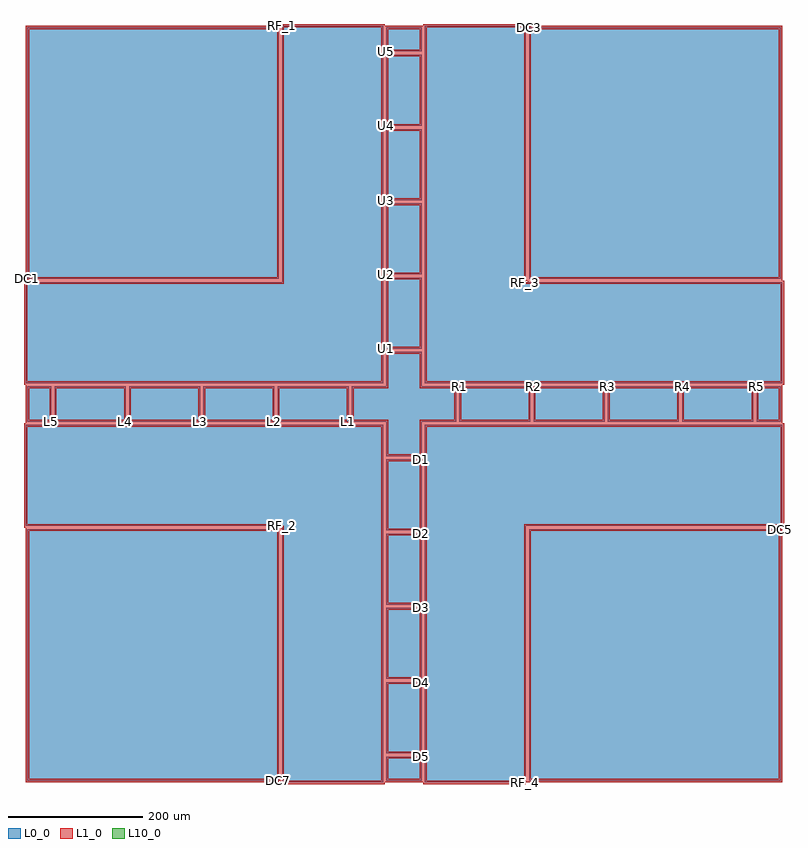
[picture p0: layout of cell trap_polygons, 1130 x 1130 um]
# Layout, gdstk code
import gdstk
lib = gdstk.Library(unit=1e-6, precision=1e-09)
def P(c, l, *ps):  # polygons
    for p in ps: c.add(gdstk.Polygon(p, *l))
L0_0 = (0, 0)
L1_0 = (1, 0)
L10_0 = (10, 0)

trap_polygons = lib.new_cell('trap_polygons')
P(trap_polygons, L0_0, [(-186.125,-560),(-560,-560),(-560,-186.125),(-186.125,-186.125),(-186.125,-560)],
  [(560,-186.125),(560,-560),(186.125,-560),(186.125,-186.125),(560,-186.125)],
  [(186.125,560),(560,560),(560,186.125),(186.125,186.125),(186.125,560)],
  [(-560,186.125),(-560,560),(-186.125,560),(-186.125,186.125),(-560,186.125)],
  [(-26.125,524.2),(-26.125,559.85),(26.125,559.85),(26.125,524.2),(-26.125,524.2)],
  [(524.2,26.125),(559.85,26.125),(559.85,-26.125),(524.2,-26.125),(524.2,26.125)],
  [(26.125,-524.2),(26.125,-559.85),(-26.125,-559.85),(-26.125,-524.2),(26.125,-524.2)],
  [(-524.2,-26.125),(-559.85,-26.125),(-559.85,26.125),(-524.2,26.125),(-524.2,-26.125)],
  [(-26.125,413.75),(-26.125,519.2),(26.125,519.2),(26.125,413.75),(-26.125,413.75)],
  [(413.75,26.125),(519.2,26.125),(519.2,-26.125),(413.75,-26.125),(413.75,26.125)],
  [(26.125,-413.75),(26.125,-519.2),(-26.125,-519.2),(-26.125,-413.75),(26.125,-413.75)],
  [(-413.75,-26.125),(-519.2,-26.125),(-519.2,26.125),(-413.75,26.125),(-413.75,-26.125)],
  [(-26.125,303.3),(-26.125,408.75),(26.125,408.75),(26.125,303.3),(-26.125,303.3)],
  [(303.3,26.125),(408.75,26.125),(408.75,-26.125),(303.3,-26.125),(303.3,26.125)],
  [(26.125,-303.3),(26.125,-408.75),(-26.125,-408.75),(-26.125,-303.3),(26.125,-303.3)],
  [(-303.3,-26.125),(-408.75,-26.125),(-408.75,26.125),(-303.3,26.125),(-303.3,-26.125)],
  [(-26.125,192.85),(-26.125,298.3),(26.125,298.3),(26.125,192.85),(-26.125,192.85)],
  [(192.85,26.125),(298.3,26.125),(298.3,-26.125),(192.85,-26.125),(192.85,26.125)],
  [(26.125,-192.85),(26.125,-298.3),(-26.125,-298.3),(-26.125,-192.85),(26.125,-192.85)],
  [(-192.85,-26.125),(-298.3,-26.125),(-298.3,26.125),(-192.85,26.125),(-192.85,-26.125)],
  [(-26.125,82.4),(-26.125,187.85),(26.125,187.85),(26.125,82.4),(-26.125,82.4)],
  [(82.4,26.125),(187.85,26.125),(187.85,-26.125),(82.4,-26.125),(82.4,26.125)],
  [(26.125,-82.4),(26.125,-187.85),(-26.125,-187.85),(-26.125,-82.4),(26.125,-82.4)],
  [(-82.4,-26.125),(-187.85,-26.125),(-187.85,26.125),(-82.4,26.125),(-82.4,-26.125)],
  [(-26.125,77.4),(26.125,77.4),(26.125,26.125),(77.4,26.125),(77.4,-26.125),(26.125,-26.125),(26.125,-77.4),(-26.125,-77.4),(-26.125,-26.125),(-77.4,-26.125),(-77.4,26.125),(-26.125,26.125),(-26.125,77.4)],
  [(181.125,-562.5),(31.125,-562.5),(31.125,-31.125),(562.5,-31.125),(562.5,-181.125),(181.125,-181.125),(181.125,-562.5)],
  [(181.125,181.125),(562.5,181.125),(562.5,31.125),(31.125,31.125),(31.125,562.5),(181.125,562.5),(181.125,181.125)],
  [(-181.125,-181.125),(-562.5,-181.125),(-562.5,-31.125),(-31.125,-31.125),(-31.125,-562.5),(-181.125,-562.5),(-181.125,-181.125)],
  [(-181.125,562.5),(-31.125,562.5),(-31.125,31.125),(-562.5,31.125),(-562.5,181.125),(-181.125,181.125),(-181.125,562.5)])
P(trap_polygons, L1_0, [(-186.125,-562.5),(-186.125,-557.5),(-557.5,-557.5),(-557.5,-188.625),(-188.625,-188.625),(-188.625,-560),(-183.625,-560),(-183.625,-183.625),(-562.5,-183.625),(-562.5,-562.5)],
  [(562.5,-186.125),(557.5,-186.125),(557.5,-557.5),(188.625,-557.5),(188.625,-188.625),(560,-188.625),(560,-183.625),(183.625,-183.625),(183.625,-562.5),(562.5,-562.5)],
  [(186.125,562.5),(186.125,557.5),(557.5,557.5),(557.5,188.625),(188.625,188.625),(188.625,560),(183.625,560),(183.625,183.625),(562.5,183.625),(562.5,562.5)],
  [(-562.5,186.125),(-557.5,186.125),(-557.5,557.5),(-188.625,557.5),(-188.625,188.625),(-560,188.625),(-560,183.625),(-183.625,183.625),(-183.625,562.5),(-562.5,562.5)],
  [(-28.625,524.2),(-23.625,524.2),(-23.625,557.35),(23.625,557.35),(23.625,526.7),(-26.125,526.7),(-26.125,521.7),(28.625,521.7),(28.625,562.35),(-28.625,562.35)],
  [(524.2,28.625),(524.2,23.625),(557.35,23.625),(557.35,-23.625),(526.7,-23.625),(526.7,26.125),(521.7,26.125),(521.7,-28.625),(562.35,-28.625),(562.35,28.625)],
  [(28.625,-524.2),(23.625,-524.2),(23.625,-557.35),(-23.625,-557.35),(-23.625,-526.7),(26.125,-526.7),(26.125,-521.7),(-28.625,-521.7),(-28.625,-562.35),(28.625,-562.35)],
  [(-524.2,-28.625),(-524.2,-23.625),(-557.35,-23.625),(-557.35,23.625),(-526.7,23.625),(-526.7,-26.125),(-521.7,-26.125),(-521.7,28.625),(-562.35,28.625),(-562.35,-28.625)],
  [(-28.625,413.75),(-23.625,413.75),(-23.625,516.7),(23.625,516.7),(23.625,416.25),(-26.125,416.25),(-26.125,411.25),(28.625,411.25),(28.625,521.7),(-28.625,521.7)],
  [(413.75,28.625),(413.75,23.625),(516.7,23.625),(516.7,-23.625),(416.25,-23.625),(416.25,26.125),(411.25,26.125),(411.25,-28.625),(521.7,-28.625),(521.7,28.625)],
  [(28.625,-413.75),(23.625,-413.75),(23.625,-516.7),(-23.625,-516.7),(-23.625,-416.25),(26.125,-416.25),(26.125,-411.25),(-28.625,-411.25),(-28.625,-521.7),(28.625,-521.7)],
  [(-413.75,-28.625),(-413.75,-23.625),(-516.7,-23.625),(-516.7,23.625),(-416.25,23.625),(-416.25,-26.125),(-411.25,-26.125),(-411.25,28.625),(-521.7,28.625),(-521.7,-28.625)],
  [(-28.625,303.3),(-23.625,303.3),(-23.625,406.25),(23.625,406.25),(23.625,305.8),(-26.125,305.8),(-26.125,300.8),(28.625,300.8),(28.625,411.25),(-28.625,411.25)],
  [(303.3,28.625),(303.3,23.625),(406.25,23.625),(406.25,-23.625),(305.8,-23.625),(305.8,26.125),(300.8,26.125),(300.8,-28.625),(411.25,-28.625),(411.25,28.625)],
  [(28.625,-303.3),(23.625,-303.3),(23.625,-406.25),(-23.625,-406.25),(-23.625,-305.8),(26.125,-305.8),(26.125,-300.8),(-28.625,-300.8),(-28.625,-411.25),(28.625,-411.25)],
  [(-303.3,-28.625),(-303.3,-23.625),(-406.25,-23.625),(-406.25,23.625),(-305.8,23.625),(-305.8,-26.125),(-300.8,-26.125),(-300.8,28.625),(-411.25,28.625),(-411.25,-28.625)],
  [(-28.625,192.85),(-23.625,192.85),(-23.625,295.8),(23.625,295.8),(23.625,195.35),(-26.125,195.35),(-26.125,190.35),(28.625,190.35),(28.625,300.8),(-28.625,300.8)],
  [(192.85,28.625),(192.85,23.625),(295.8,23.625),(295.8,-23.625),(195.35,-23.625),(195.35,26.125),(190.35,26.125),(190.35,-28.625),(300.8,-28.625),(300.8,28.625)],
  [(28.625,-192.85),(23.625,-192.85),(23.625,-295.8),(-23.625,-295.8),(-23.625,-195.35),(26.125,-195.35),(26.125,-190.35),(-28.625,-190.35),(-28.625,-300.8),(28.625,-300.8)],
  [(-192.85,-28.625),(-192.85,-23.625),(-295.8,-23.625),(-295.8,23.625),(-195.35,23.625),(-195.35,-26.125),(-190.35,-26.125),(-190.35,28.625),(-300.8,28.625),(-300.8,-28.625)],
  [(-28.625,82.4),(-23.625,82.4),(-23.625,185.35),(23.625,185.35),(23.625,84.9),(-26.125,84.9),(-26.125,79.9),(28.625,79.9),(28.625,190.35),(-28.625,190.35)],
  [(82.4,28.625),(82.4,23.625),(185.35,23.625),(185.35,-23.625),(84.9,-23.625),(84.9,26.125),(79.9,26.125),(79.9,-28.625),(190.35,-28.625),(190.35,28.625)],
  [(28.625,-82.4),(23.625,-82.4),(23.625,-185.35),(-23.625,-185.35),(-23.625,-84.9),(26.125,-84.9),(26.125,-79.9),(-28.625,-79.9),(-28.625,-190.35),(28.625,-190.35)],
  [(-82.4,-28.625),(-82.4,-23.625),(-185.35,-23.625),(-185.35,23.625),(-84.9,23.625),(-84.9,-26.125),(-79.9,-26.125),(-79.9,28.625),(-190.35,28.625),(-190.35,-28.625)],
  [(-26.125,79.9),(-26.125,74.9),(23.625,74.9),(23.625,23.625),(74.9,23.625),(74.9,-23.625),(23.625,-23.625),(23.625,-74.9),(-23.625,-74.9),(-23.625,-23.625),(-74.9,-23.625),(-74.9,23.625),(-23.625,23.625),(-23.625,77.4),(-28.625,77.4),(-28.625,28.625),(-79.9,28.625),(-79.9,-28.625),(-28.625,-28.625),(-28.625,-79.9),(28.625,-79.9),(28.625,-28.625),(79.9,-28.625),(79.9,28.625),(28.625,28.625),(28.625,79.9)],
  [(181.125,-565),(181.125,-560),(33.625,-560),(33.625,-33.625),(560,-33.625),(560,-178.625),(178.625,-178.625),(178.625,-562.5),(183.625,-562.5),(183.625,-183.625),(565,-183.625),(565,-28.625),(28.625,-28.625),(28.625,-565)],
  [(181.125,183.625),(181.125,178.625),(560,178.625),(560,33.625),(33.625,33.625),(33.625,560),(178.625,560),(178.625,181.125),(183.625,181.125),(183.625,565),(28.625,565),(28.625,28.625),(565,28.625),(565,183.625)],
  [(-181.125,-183.625),(-181.125,-178.625),(-560,-178.625),(-560,-33.625),(-33.625,-33.625),(-33.625,-560),(-178.625,-560),(-178.625,-181.125),(-183.625,-181.125),(-183.625,-565),(-28.625,-565),(-28.625,-28.625),(-565,-28.625),(-565,-183.625)],
  [(-181.125,565),(-181.125,560),(-33.625,560),(-33.625,33.625),(-560,33.625),(-560,178.625),(-178.625,178.625),(-178.625,562.5),(-183.625,562.5),(-183.625,183.625),(-565,183.625),(-565,28.625),(-28.625,28.625),(-28.625,565)])
P(trap_polygons, L10_0, [(0,0),(0,0),(0,0),(0,0)])
trap_polygons.add(gdstk.Label('DC7', (-186.125,-560), layer=2, texttype=0))
trap_polygons.add(gdstk.Label('DC5', (560,-186.125), layer=2, texttype=0))
trap_polygons.add(gdstk.Label('DC3', (186.125,560), layer=2, texttype=0))
trap_polygons.add(gdstk.Label('DC1', (-560,186.125), layer=2, texttype=0))
trap_polygons.add(gdstk.Label('U5', (-26.125,524.2), layer=2, texttype=0))
trap_polygons.add(gdstk.Label('R5', (524.2,26.125), layer=2, texttype=0))
trap_polygons.add(gdstk.Label('D5', (26.125,-524.2), layer=2, texttype=0))
trap_polygons.add(gdstk.Label('L5', (-524.2,-26.125), layer=2, texttype=0))
trap_polygons.add(gdstk.Label('U4', (-26.125,413.75), layer=2, texttype=0))
trap_polygons.add(gdstk.Label('R4', (413.75,26.125), layer=2, texttype=0))
trap_polygons.add(gdstk.Label('D4', (26.125,-413.75), layer=2, texttype=0))
trap_polygons.add(gdstk.Label('L4', (-413.75,-26.125), layer=2, texttype=0))
trap_polygons.add(gdstk.Label('U3', (-26.125,303.3), layer=2, texttype=0))
trap_polygons.add(gdstk.Label('R3', (303.3,26.125), layer=2, texttype=0))
trap_polygons.add(gdstk.Label('D3', (26.125,-303.3), layer=2, texttype=0))
trap_polygons.add(gdstk.Label('L3', (-303.3,-26.125), layer=2, texttype=0))
trap_polygons.add(gdstk.Label('U2', (-26.125,192.85), layer=2, texttype=0))
trap_polygons.add(gdstk.Label('R2', (192.85,26.125), layer=2, texttype=0))
trap_polygons.add(gdstk.Label('D2', (26.125,-192.85), layer=2, texttype=0))
trap_polygons.add(gdstk.Label('L2', (-192.85,-26.125), layer=2, texttype=0))
trap_polygons.add(gdstk.Label('U1', (-26.125,82.4), layer=2, texttype=0))
trap_polygons.add(gdstk.Label('R1', (82.4,26.125), layer=2, texttype=0))
trap_polygons.add(gdstk.Label('D1', (26.125,-82.4), layer=2, texttype=0))
trap_polygons.add(gdstk.Label('L1', (-82.4,-26.125), layer=2, texttype=0))
trap_polygons.add(gdstk.Label('C', (-26.125,77.4), layer=2, texttype=0))
trap_polygons.add(gdstk.Label('RF_4', (181.125,-562.5), layer=2, texttype=0))
trap_polygons.add(gdstk.Label('RF_3', (181.125,181.125), layer=2, texttype=0))
trap_polygons.add(gdstk.Label('RF_2', (-181.125,-181.125), layer=2, texttype=0))
trap_polygons.add(gdstk.Label('RF_1', (-181.125,562.5), layer=2, texttype=0))

lib.write_gds('trap_polygons.gds')
